VERSION 5.8 ;
BUSBITCHARS "<>" ;
DIVIDERCHAR "/" ;

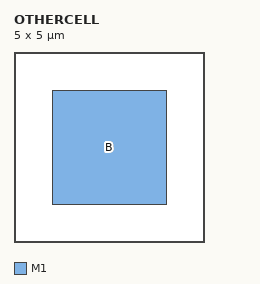
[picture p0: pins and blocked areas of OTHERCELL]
MACRO OTHERCELL
   CLASS CORE ;
   SIZE 5 BY 5 ;

   PIN B
      DIRECTION OUTPUT ;
      PORT
         LAYER M1 ;
         RECT 1 1 4 4 ;
      END
   END B
END OTHERCELL
